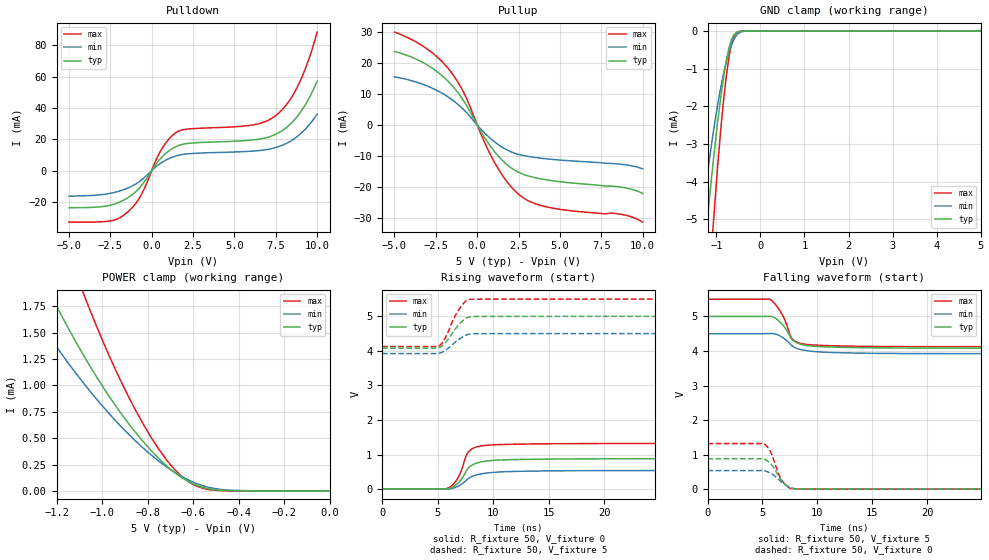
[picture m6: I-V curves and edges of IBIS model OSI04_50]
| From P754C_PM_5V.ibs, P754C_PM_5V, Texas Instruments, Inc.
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[Model]   OSI04_50
Model_type  3-state
Enable   Active-Low
Vref =   2.5
Rref =   50
Cref =   15p
Vmeas =   2.5
| variable   typ   min   max
C_comp   0.90pF   0.60pF   1.13pF
| C_pullup   1.10pF   0.59pF   1.42pF
| C_pulldown   1.05pF   0.71pF   1.33pF
| C_tri-state   0.90pF   0.60pF   1.13pF
[Temperature Range]   40   125   -40
| Ambient temperature   25   110   -40
[Voltage range]   5   4.5   5.5
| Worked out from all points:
|   slope of the pulldown table from 0 to 0.75 V, typ, clamps not added: 74.7 ohm
|   slope of the pullup table from 0 to 0.75 V, typ, clamps not added: 115 ohm
|   GND clamp passes 1 mA (typ) near -0.81 V on its own axis
|   POWER clamp passes 1 mA (typ) near -1.00 V on its own axis
|   rising waveform, R_fixture 50, V_fixture 0: 20-80 % time 1.32ns typ, 1.79ns min, 1.01ns max; typ from 0.001 V to 0.88 V
|   falling waveform, R_fixture 50, V_fixture 5: 20-80 % time 1.3ns typ, 1.67ns min, 1.15ns max; typ from 5 V to 4.08 V
|   rising waveform, R_fixture 50, V_fixture 5: 20-80 % time 1.3ns typ, 1.36ns min, 1.24ns max; typ from 4.08 V to 5 V
|   falling waveform, R_fixture 50, V_fixture 0: 20-80 % time 1.12ns typ, 1.27ns min, 984ps max; typ from 0.881 V to 0.001 V
[GND Clamp]
| OSI04_50
|   Voltage   I(typ)   I(min)   I(max)
-5V       -71.14mA   -54.85mA   -93.73mA
-1.37V    -7.137mA   -5.341mA   -10.51mA
-1.325V   -6.536mA   -4.906mA   -9.646mA
-1.245V   -5.505mA   -4.162mA   -8.155mA
-1.205V   -5.008mA   -3.804mA   -7.431mA
-1.075V   -3.493mA   -2.721mA   -5.198mA
-905mV    -1.792mA   -1.52mA    -2.668mA
-775mV    -790.8uA   -815uA     -1.203mA
-655mV    -225.3uA   -360.8uA   -339.3uA
-525mV    -26.91uA   -88.48uA   -31.35uA
-270mV    -69.28nA   -428.3nA   -21.58nA
5V        307.6pA    20.19uA    199pA
[POWER Clamp]
| OSI04_50
|   Voltage   I(typ)   I(min)   I(max)
-5V       40.39mA    30.49mA    53.4mA
-1.365V   2.49mA     1.904mA    3.667mA
-1.33V    2.325mA    1.783mA    3.423mA
-1.235V   1.899mA    1.473mA    2.79mA
-1.205V   1.772mA    1.38mA     2.599mA
-1.085V   1.298mA    1.031mA    1.888mA
-940mV    805.6uA    663.8uA    1.144mA
-820mV    469.2uA    407.7uA    636.6uA
-715mV    235.1uA    225.3uA    290uA
-650mV    126.3uA    136.4uA    138.4uA
-525mV    18.24uA    30.51uA    10.98uA
-84.4fV   307.6pA    1.278nA    227.9pA
[Pulldown]
| OSI04_50
|   Voltage   I(typ)   I(min)   I(max)
-5V       -23.66mA   -16.28mA   -32.78mA
-2.52V    -22.12mA   -14.49mA   -32.12mA
-1.515V   -17.77mA   -11.42mA   -26.98mA
-650mV    -10.01mA   -6.221mA   -15.81mA
660mV     9.077mA    5.521mA    14.67mA
1.59V     15.87mA    9.709mA    25.04mA
6.11V     19.58mA    12.47mA    29.13mA
7.495V    23.19mA    14.72mA    35.12mA
8.195V    27.92mA    17.66mA    42.77mA
8.83V     34.94mA    22.06mA    53.92mA
9.43V     44.62mA    28.14mA    69.08mA
10V       57.05mA    36mA       88.35mA
[Pullup]
| OSI04_50
|   Voltage   I(typ)   I(min)   I(max)
-5V       23.78mA    15.59mA    30.03mA
-3.07V    19.58mA    12.72mA    24.75mA
-1.615V   13.33mA    8.548mA    17.36mA
-750mV    7.259mA    4.617mA    9.798mA
385mV     -3.521mA   -2.215mA   -4.882mA
1.09V     -8.864mA   -5.585mA   -12.48mA
1.86V     -13.04mA   -8.177mA   -18.72mA
2.64V     -15.6mA    -9.648mA   -22.93mA
3.32V     -16.75mA   -10.31mA   -25.02mA
4.25V     -17.74mA   -10.94mA   -26.5mA
8.625V    -19.99mA   -12.62mA   -28.76mA
10V       -22.08mA   -14.12mA   -31.36mA
[Ramp]
| OSI04_50
| variable   typ   min   max
dV/dt_r   0.50/1.27E-09   0.31/1.79E-09   0.73/9.28E-10
dV/dt_f   0.51/1.23E-09   0.34/1.67E-09   0.71/9.45E-10
R_load = 50
[Rising Waveform]
| OSI04_50
R_fixture =   50
C_fixture =   0
L_fixture =   0
V_fixture =   0
V_fixture_min = 0
V_fixture_max = 0
|   Time   V(typ)   V(min)   V(max)
0s        1.02mV     790.7uV    1.331mV
5.895ns   5.72mV     -767.9uV   23.79mV
6.4ns     65.53mV    26.93mV    139.5mV
6.845ns   174.1mV    83.66mV    330.2mV
7.12ns    274.6mV    134.8mV    521.7mV
7.565ns   517.2mV    250.6mV    957.1mV
7.775ns   609.6mV    304.7mV    1.074V
9.04ns    794.4mV    446.6mV    1.253V
13.79ns   862.7mV    521.1mV    1.307V
31.25ns   880.4mV    537.9mV    1.321V
[Falling Waveform]
| OSI04_50
R_fixture =   50
C_fixture =   0
L_fixture =   0
V_fixture =   5
V_fixture_min = 4.5
V_fixture_max = 5.5
|   Time   V(typ)   V(min)   V(max)
0s        4.999V     4.499V     5.498V
5.7ns     5.003V     4.503V     5.491V
6.175ns   4.952V     4.492V     5.348V
6.785ns   4.775V     4.402V     5.061V
7.08ns    4.657V     4.334V     4.866V
7.695ns   4.335V     4.152V     4.362V
8.185ns   4.228V     4.069V     4.25V
8.95ns    4.163V     4.013V     4.193V
14.57ns   4.093V     3.935V     4.133V
31.25ns   4.08V      3.922V     4.124V
[Rising Waveform]
| OSI04_50
R_fixture =   50
C_fixture =   0
L_fixture =   0
V_fixture =   5
V_fixture_min = 4.5
V_fixture_max = 5.5
|   Time   V(typ)   V(min)   V(max)
0s        4.08V      3.921V     4.124V
5.1ns     4.085V     3.925V     4.134V
5.36ns    4.133V     3.954V     4.213V
5.68ns    4.228V     4.012V     4.365V
6.395ns   4.549V     4.198V     4.892V
6.85ns    4.734V     4.317V     5.162V
7.475ns   4.929V     4.441V     5.423V
7.82ns    4.981V     4.479V     5.485V
9.93ns    4.997V     4.497V     5.496V
31.25ns   4.999V     4.499V     5.498V
[Falling Waveform]
| OSI04_50
R_fixture =   50
C_fixture =   0
L_fixture =   0
V_fixture =   0
V_fixture_min = 0
V_fixture_max = 0
|   Time   V(typ)   V(min)   V(max)
0s        881.1mV    538.4mV    1.321V
5.135ns   874.7mV    535.5mV    1.31V
5.475ns   812.9mV    502mV      1.211V
5.77ns    728mV      455.6mV    1.061V
6.435ns   397.3mV    290.9mV    469.6mV
6.74ns    256.4mV    205.7mV    275.6mV
7.22ns    103.3mV    100.2mV    91.99mV
7.695ns   23.22mV    33.22mV    12.55mV
9.41ns    3.431mV    3.291mV    3.843mV
31.25ns   1.061mV    817.6uV    1.347mV
